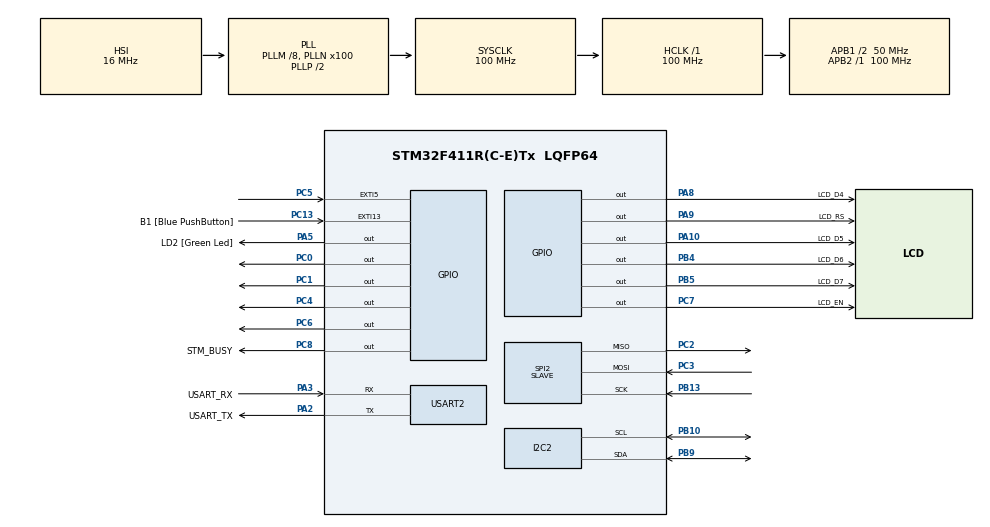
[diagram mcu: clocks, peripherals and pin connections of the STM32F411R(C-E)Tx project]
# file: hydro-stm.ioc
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Mcu.Family=STM32F4
Mcu.Name=STM32F411R(C-E)Tx
Mcu.Package=LQFP64
NVIC.EXTI9_5_IRQn=true\:0\:0\:false\:false\:true\:true\:true\:true
NVIC.PriorityGroup=NVIC_PRIORITYGROUP_0
NVIC.SPI2_IRQn=true\:0\:0\:false\:false\:true\:true\:true\:true
PA10.GPIO_Label=LCD_D5
PA10.Signal=GPIO_Output
PA13.GPIO_Label=TMS
PA13.Mode=Serial_Wire
PA13.Signal=SYS_JTMS-SWDIO
PA14.GPIO_Label=TCK
PA14.Mode=Serial_Wire
PA14.Signal=SYS_JTCK-SWCLK
PA2.GPIO_Label=USART_TX
PA2.Mode=Asynchronous
PA2.Signal=USART2_TX
PA3.GPIO_Label=USART_RX
PA3.Mode=Asynchronous
PA3.Signal=USART2_RX
PA5.GPIO_Label=LD2 [Green Led]
PA5.Signal=GPIO_Output
PA8.GPIO_Label=LCD_D4
PA8.Signal=GPIO_Output
PA9.GPIO_Label=LCD_RS
PA9.Signal=GPIO_Output
PB10.Mode=I2C
PB10.Signal=I2C2_SCL
PB13.Mode=Full_Duplex_Slave
PB13.Signal=SPI2_SCK
PB3.GPIO_Label=SWO
PB3.Signal=SYS_JTDO-SWO
PB4.GPIO_Label=LCD_D6
PB4.Signal=GPIO_Output
PB5.GPIO_Label=LCD_D7
PB5.Signal=GPIO_Output
PB6.Signal=I2C1_SCL
PB9.Mode=I2C
PB9.Signal=I2C2_SDA
PC0.Signal=GPIO_Output
PC1.Signal=GPIO_Output
PC13-ANTI_TAMP.GPIO_Label=B1 [Blue PushButton]
PC13-ANTI_TAMP.GPIO_ModeDefaultEXTI=GPIO_MODE_IT_FALLING
PC13-ANTI_TAMP.Signal=GPXTI13
PC14-OSC32_IN.Mode=LSE-External-Oscillator
PC14-OSC32_IN.Signal=RCC_OSC32_IN
PC15-OSC32_OUT.Mode=LSE-External-Oscillator
PC15-OSC32_OUT.Signal=RCC_OSC32_OUT
PC2.Mode=Full_Duplex_Slave
PC2.Signal=SPI2_MISO
PC3.Mode=Full_Duplex_Slave
PC3.Signal=SPI2_MOSI
PC4.Signal=GPIO_Output
PC5.Signal=GPXTI5
PC6.Signal=GPIO_Output
PC7.GPIO_Label=LCD_EN
PC7.Signal=GPIO_Output
PC8.GPIO_Label=STM_BUSY
PC8.Signal=GPIO_Output
PH0\ -\ OSC_IN.Mode=HSE-External-Clock-Source
PH0\ -\ OSC_IN.Signal=RCC_OSC_IN
PH1\ -\ OSC_OUT.Mode=HSE-External-Clock-Source
PH1\ -\ OSC_OUT.Signal=RCC_OSC_OUT
ProjectManager.HeapSize=0x200
ProjectManager.StackSize=0x400
ProjectManager.TargetToolchain=STM32CubeIDE
RCC.48MHZClocksFreq_Value=50000000
RCC.AHBFreq_Value=100000000
RCC.APB1CLKDivider=RCC_HCLK_DIV2
RCC.APB1Freq_Value=50000000
RCC.APB1TimFreq_Value=100000000
RCC.APB2Freq_Value=100000000
RCC.APB2TimFreq_Value=100000000
RCC.CortexFreq_Value=100000000
RCC.FLatency-AdvancedSettings=FLASH_LATENCY_3
RCC.HCLKFreq_Value=100000000
RCC.HSE_VALUE=8000000
RCC.HSI_VALUE=16000000
RCC.PLLM=8
RCC.PLLN=100
RCC.SYSCLKFreq_VALUE=100000000
RCC.SYSCLKSource=RCC_SYSCLKSOURCE_PLLCLK
RCC.VCOOutputFreq_Value=200000000
SPI2.DataSize=SPI_DATASIZE_8BIT
SPI2.Direction=SPI_DIRECTION_2LINES
SPI2.Mode=SPI_MODE_SLAVE
SPI2.VirtualType=VM_SLAVE
USART2.VirtualMode=VM_ASYNC
board=NUCLEO-F411RE

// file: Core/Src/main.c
/* USER CODE BEGIN Header */
/**
  ******************************************************************************
  * @file           : main.c
  * @brief          : Main program body
  ******************************************************************************
  * @attention
  *
  * Copyright (c) 2025 STMicroelectronics.
  * All rights reserved.
  *
  * This software is licensed under terms that can be found in the LICENSE file
  * in the root directory of this software component.
  * If no LICENSE file comes with this software, it is provided AS-IS.
  *
  ******************************************************************************
  */
/* USER CODE END Header */
#include "main.h"

/* USER CODE BEGIN Includes */
#include "scheduler.h"
#include "sensor_manager.h"
#include "comm_manager.h"
#include "LCD.h"

//Sensors
#include "bmp180.h"
/* USER CODE END Includes */

I2C_HandleTypeDef hi2c2;

SPI_HandleTypeDef hspi2;

UART_HandleTypeDef huart2;

/* USER CODE BEGIN PV */
//size_t BUFFER_SIZE = 4;
//uint8_t spi2tx_buffer[4] = {0xAA, 0xAA, 0xAA, 0xAA};
//uint8_t spi2rx_buffer[4] = {0};
/* USER CODE END PV */

void SystemClock_Config(void);
static void MX_GPIO_Init(void);
static void MX_USART2_UART_Init(void);
static void MX_I2C2_Init(void);
static void MX_SPI2_Init(void);

/* USER CODE BEGIN 0 */
//Sensor wiring
void BMP_Init(I2C_HandleTypeDef *i2c_loc){
  BMP180_Init(i2c_loc);
  BMP180_SetOversampling(BMP180_STANDARD);
  BMP180_UpdateCalibrationData();
}

void AllSensor_Init(void){
  BMP_Init(&hi2c2);
}

uint8_t txBuff[11] = {0xAA, 0xBB, 0xCC, 0xDD, 0x11, 0x22};
uint8_t rxBuff[11] = {0};
const uint32_t SPI_TIMEOUT = 30;

void InitializeSPI(void){
  Comm_PassRxBufferPtr(rxBuff);
  Comm_UpdateSPISnapshot();
  const SystemSnapshot_t *snap = &snapActive;
  memcpy(txBuff, snap, sizeof(SystemSnapshot_t));
  HAL_GPIO_WritePin(GPIOC, GPIO_PIN_8, GPIO_PIN_SET);
  HAL_SPI_TransmitReceive(&hspi2, txBuff, rxBuff, 11, SPI_TIMEOUT);
  HAL_GPIO_WritePin(GPIOC, GPIO_PIN_8, GPIO_PIN_RESET);

  //Do below only when CRC is not correct
  //HAL_SPI_Abort(&hspi2);      // stop ongoing transfer (blocking)
  HAL_SPI_DeInit(&hspi2);     // reset peripheral state
  HAL_SPI_Init(&hspi2);       // reinitialize
  //Comm_HandleSPIData();
}
/* USER CODE END 0 */

int main(void)
{

  /* MCU Configuration--------------------------------------------------------*/

  /* Reset of all peripherals, Initializes the Flash interface and the Systick. */
  HAL_Init();

  /* Configure the system clock */
  SystemClock_Config();

  /* Initialize all configured peripherals */
  MX_GPIO_Init();
  MX_USART2_UART_Init();
  MX_I2C2_Init();
  MX_SPI2_Init();
  /* USER CODE BEGIN 2 */
  Sensor_Init();
  AllSensor_Init();
  Scheduler_Init();
  LCD_Init();
  int lel = 2;
  if (HAL_I2C_IsDeviceReady(&hi2c2, 0x77<<1, 3, 100) != HAL_OK) {
      lel = 0;
  }

  /* USER CODE END 2 */

  /* Infinite loop */
  /* USER CODE BEGIN WHILE */
  while (1)
  {
	Scheduler_Run();

	lel++;
	if(HAL_GPIO_ReadPin(GPIOC, GPIO_PIN_13) == GPIO_PIN_RESET){
		HAL_GPIO_TogglePin(GPIOA, GPIO_PIN_5);
		HAL_Delay(300);
	}

    //HAL_SPI_TransmitReceive(&hspi2, spi2tx_buffer, spi2rx_buffer, 4, HAL_MAX_DELAY);
	//HAL_Delay(1000);
    /* USER CODE END WHILE */

  }
}

void SystemClock_Config(void)
{
  RCC_OscInitTypeDef RCC_OscInitStruct = {0};
  RCC_ClkInitTypeDef RCC_ClkInitStruct = {0};

  /** Configure the main internal regulator output voltage
  */
  __HAL_RCC_PWR_CLK_ENABLE();
  __HAL_PWR_VOLTAGESCALING_CONFIG(PWR_REGULATOR_VOLTAGE_SCALE1);

  /** Initializes the RCC Oscillators according to the specified parameters
  * in the RCC_OscInitTypeDef structure.
  */
  RCC_OscInitStruct.OscillatorType = RCC_OSCILLATORTYPE_HSI;
  RCC_OscInitStruct.HSIState = RCC_HSI_ON;
  RCC_OscInitStruct.HSICalibrationValue = RCC_HSICALIBRATION_DEFAULT;
  RCC_OscInitStruct.PLL.PLLState = RCC_PLL_ON;
  RCC_OscInitStruct.PLL.PLLSource = RCC_PLLSOURCE_HSI;
  RCC_OscInitStruct.PLL.PLLM = 8;
  RCC_OscInitStruct.PLL.PLLN = 100;
  RCC_OscInitStruct.PLL.PLLP = RCC_PLLP_DIV2;
  RCC_OscInitStruct.PLL.PLLQ = 4;
  if (HAL_RCC_OscConfig(&RCC_OscInitStruct) != HAL_OK)
  {
    Error_Handler();
  }

  /** Initializes the CPU, AHB and APB buses clocks
  */
  RCC_ClkInitStruct.ClockType = RCC_CLOCKTYPE_HCLK|RCC_CLOCKTYPE_SYSCLK
                              |RCC_CLOCKTYPE_PCLK1|RCC_CLOCKTYPE_PCLK2;
  RCC_ClkInitStruct.SYSCLKSource = RCC_SYSCLKSOURCE_PLLCLK;
  RCC_ClkInitStruct.AHBCLKDivider = RCC_SYSCLK_DIV1;
  RCC_ClkInitStruct.APB1CLKDivider = RCC_HCLK_DIV2;
  RCC_ClkInitStruct.APB2CLKDivider = RCC_HCLK_DIV1;

  if (HAL_RCC_ClockConfig(&RCC_ClkInitStruct, FLASH_LATENCY_3) != HAL_OK)
  {
    Error_Handler();
  }
}

static void MX_I2C2_Init(void)
{

  hi2c2.Instance = I2C2;
  hi2c2.Init.ClockSpeed = 100000;
  hi2c2.Init.DutyCycle = I2C_DUTYCYCLE_2;
  hi2c2.Init.OwnAddress1 = 0;
  hi2c2.Init.AddressingMode = I2C_ADDRESSINGMODE_7BIT;
  hi2c2.Init.DualAddressMode = I2C_DUALADDRESS_DISABLE;
  hi2c2.Init.OwnAddress2 = 0;
  hi2c2.Init.GeneralCallMode = I2C_GENERALCALL_DISABLE;
  hi2c2.Init.NoStretchMode = I2C_NOSTRETCH_DISABLE;
  if (HAL_I2C_Init(&hi2c2) != HAL_OK)
  {
    Error_Handler();
  }

}

static void MX_SPI2_Init(void)
{

  /* SPI2 parameter configuration*/
  hspi2.Instance = SPI2;
  hspi2.Init.Mode = SPI_MODE_SLAVE;
  hspi2.Init.Direction = SPI_DIRECTION_2LINES;
  hspi2.Init.DataSize = SPI_DATASIZE_8BIT;
  hspi2.Init.CLKPolarity = SPI_POLARITY_LOW;
  hspi2.Init.CLKPhase = SPI_PHASE_1EDGE;
  hspi2.Init.NSS = SPI_NSS_SOFT;
  hspi2.Init.FirstBit = SPI_FIRSTBIT_MSB;
  hspi2.Init.TIMode = SPI_TIMODE_DISABLE;
  hspi2.Init.CRCCalculation = SPI_CRCCALCULATION_DISABLE;
  hspi2.Init.CRCPolynomial = 10;
  if (HAL_SPI_Init(&hspi2) != HAL_OK)
  {
    Error_Handler();
  }

}

static void MX_USART2_UART_Init(void)
{

  huart2.Instance = USART2;
  huart2.Init.BaudRate = 115200;
  huart2.Init.WordLength = UART_WORDLENGTH_8B;
  huart2.Init.StopBits = UART_STOPBITS_1;
  huart2.Init.Parity = UART_PARITY_NONE;
  huart2.Init.Mode = UART_MODE_TX_RX;
  huart2.Init.HwFlowCtl = UART_HWCONTROL_NONE;
  huart2.Init.OverSampling = UART_OVERSAMPLING_16;
  if (HAL_UART_Init(&huart2) != HAL_OK)
  {
    Error_Handler();
  }

}

static void MX_GPIO_Init(void)
{
  GPIO_InitTypeDef GPIO_InitStruct = {0};

  /* GPIO Ports Clock Enable */
  __HAL_RCC_GPIOC_CLK_ENABLE();
  __HAL_RCC_GPIOH_CLK_ENABLE();
  __HAL_RCC_GPIOA_CLK_ENABLE();
  __HAL_RCC_GPIOB_CLK_ENABLE();

  /*Configure GPIO pin Output Level */
  HAL_GPIO_WritePin(GPIOC, GPIO_PIN_0|GPIO_PIN_1|GPIO_PIN_4|GPIO_PIN_6
                          |LCD_EN_Pin|STM_READY_Pin, GPIO_PIN_RESET);

  /*Configure GPIO pin Output Level */
  HAL_GPIO_WritePin(GPIOA, LD2_Pin|LCD_D4_Pin|LCD_RS_Pin|LCD_D5_Pin, GPIO_PIN_RESET);

  /*Configure GPIO pin Output Level */
  HAL_GPIO_WritePin(GPIOB, LCD_D6_Pin|LCD_D7_Pin, GPIO_PIN_RESET);

  /*Configure GPIO pin : B1_Pin */
  GPIO_InitStruct.Pin = B1_Pin;
  GPIO_InitStruct.Mode = GPIO_MODE_IT_FALLING;
  GPIO_InitStruct.Pull = GPIO_NOPULL;
  HAL_GPIO_Init(B1_GPIO_Port, &GPIO_InitStruct);

  /*Configure GPIO pins : PC0 PC1 PC4 PC6
                           LCD_EN_Pin STM_READY_Pin */
  GPIO_InitStruct.Pin = GPIO_PIN_0|GPIO_PIN_1|GPIO_PIN_4|GPIO_PIN_6
                          |LCD_EN_Pin|STM_READY_Pin;
  GPIO_InitStruct.Mode = GPIO_MODE_OUTPUT_PP;
  GPIO_InitStruct.Pull = GPIO_NOPULL;
  GPIO_InitStruct.Speed = GPIO_SPEED_FREQ_LOW;
  HAL_GPIO_Init(GPIOC, &GPIO_InitStruct);

  /*Configure GPIO pins : LD2_Pin LCD_D4_Pin LCD_RS_Pin LCD_D5_Pin */
  GPIO_InitStruct.Pin = LD2_Pin|LCD_D4_Pin|LCD_RS_Pin|LCD_D5_Pin;
  GPIO_InitStruct.Mode = GPIO_MODE_OUTPUT_PP;
  GPIO_InitStruct.Pull = GPIO_NOPULL;
  GPIO_InitStruct.Speed = GPIO_SPEED_FREQ_LOW;
  HAL_GPIO_Init(GPIOA, &GPIO_InitStruct);

  /*Configure GPIO pin : COMM_REQUST_Pin */
  GPIO_InitStruct.Pin = COMM_REQUST_Pin;
  GPIO_InitStruct.Mode = GPIO_MODE_INPUT;
  GPIO_InitStruct.Pull = GPIO_NOPULL;
  HAL_GPIO_Init(COMM_REQUST_GPIO_Port, &GPIO_InitStruct);

  /*Configure GPIO pins : LCD_D6_Pin LCD_D7_Pin */
  GPIO_InitStruct.Pin = LCD_D6_Pin|LCD_D7_Pin;
  GPIO_InitStruct.Mode = GPIO_MODE_OUTPUT_PP;
  GPIO_InitStruct.Pull = GPIO_NOPULL;
  GPIO_InitStruct.Speed = GPIO_SPEED_FREQ_LOW;
  HAL_GPIO_Init(GPIOB, &GPIO_InitStruct);

  /*Configure GPIO pin : PB6 */
  GPIO_InitStruct.Pin = GPIO_PIN_6;
  GPIO_InitStruct.Mode = GPIO_MODE_AF_OD;
  GPIO_InitStruct.Pull = GPIO_NOPULL;
  GPIO_InitStruct.Speed = GPIO_SPEED_FREQ_VERY_HIGH;
  GPIO_InitStruct.Alternate = GPIO_AF4_I2C1;
  HAL_GPIO_Init(GPIOB, &GPIO_InitStruct);

}

void Error_Handler(void)
{
  __disable_irq();
  while (1)
  {
  }
}
